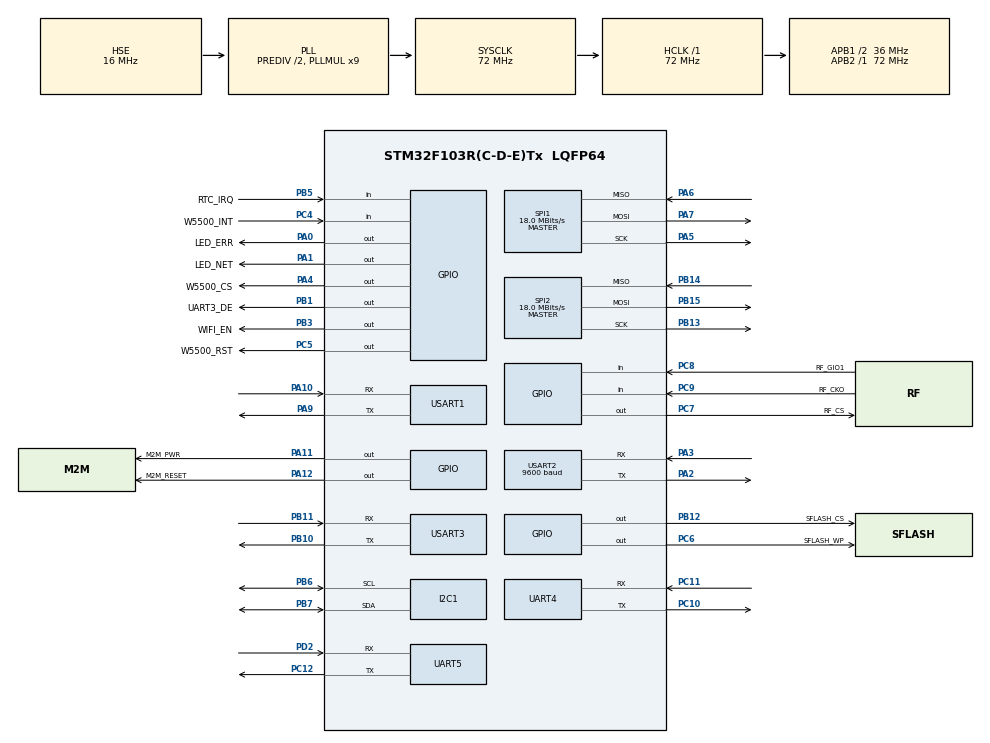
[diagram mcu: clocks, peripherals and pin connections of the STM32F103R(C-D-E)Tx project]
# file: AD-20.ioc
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Dma.Request0=USART1_TX
Dma.Request1=USART3_TX
Dma.Request2=USART2_TX
Dma.Request3=UART4_TX
Dma.UART4_TX.3.Direction=DMA_MEMORY_TO_PERIPH
Dma.UART4_TX.3.Instance=DMA2_Channel5
Dma.UART4_TX.3.MemDataAlignment=DMA_MDATAALIGN_BYTE
Dma.UART4_TX.3.MemInc=DMA_MINC_ENABLE
Dma.UART4_TX.3.Mode=DMA_NORMAL
Dma.UART4_TX.3.PeriphDataAlignment=DMA_PDATAALIGN_BYTE
Dma.UART4_TX.3.PeriphInc=DMA_PINC_DISABLE
Dma.UART4_TX.3.Priority=DMA_PRIORITY_LOW
Dma.USART1_TX.0.Direction=DMA_MEMORY_TO_PERIPH
Dma.USART1_TX.0.Instance=DMA1_Channel4
Dma.USART1_TX.0.MemDataAlignment=DMA_MDATAALIGN_BYTE
Dma.USART1_TX.0.MemInc=DMA_MINC_ENABLE
Dma.USART1_TX.0.Mode=DMA_NORMAL
Dma.USART1_TX.0.PeriphDataAlignment=DMA_PDATAALIGN_BYTE
Dma.USART1_TX.0.PeriphInc=DMA_PINC_DISABLE
Dma.USART1_TX.0.Priority=DMA_PRIORITY_LOW
Dma.USART2_TX.2.Direction=DMA_MEMORY_TO_PERIPH
Dma.USART2_TX.2.Instance=DMA1_Channel7
Dma.USART2_TX.2.MemDataAlignment=DMA_MDATAALIGN_BYTE
Dma.USART2_TX.2.MemInc=DMA_MINC_ENABLE
Dma.USART2_TX.2.Mode=DMA_NORMAL
Dma.USART2_TX.2.PeriphDataAlignment=DMA_PDATAALIGN_BYTE
Dma.USART2_TX.2.PeriphInc=DMA_PINC_DISABLE
Dma.USART2_TX.2.Priority=DMA_PRIORITY_LOW
Dma.USART3_TX.1.Direction=DMA_MEMORY_TO_PERIPH
Dma.USART3_TX.1.Instance=DMA1_Channel2
Dma.USART3_TX.1.MemDataAlignment=DMA_MDATAALIGN_BYTE
Dma.USART3_TX.1.MemInc=DMA_MINC_ENABLE
Dma.USART3_TX.1.Mode=DMA_NORMAL
Dma.USART3_TX.1.PeriphDataAlignment=DMA_PDATAALIGN_BYTE
Dma.USART3_TX.1.PeriphInc=DMA_PINC_DISABLE
Dma.USART3_TX.1.Priority=DMA_PRIORITY_LOW
FREERTOS.Tasks01=defaultTask,0,128,StartDefaultTask,Default,NULL
FREERTOS.configCHECK_FOR_STACK_OVERFLOW=2
FREERTOS.configQUEUE_REGISTRY_SIZE=16
FREERTOS.configTOTAL_HEAP_SIZE=30720
FREERTOS.configUSE_IDLE_HOOK=1
FREERTOS.configUSE_MALLOC_FAILED_HOOK=1
FREERTOS.configUSE_RECURSIVE_MUTEXES=1
FREERTOS.configUSE_TICK_HOOK=1
IWDG.Prescaler=IWDG_PRESCALER_128
Mcu.Family=STM32F1
Mcu.Name=STM32F103R(C-D-E)Tx
Mcu.Package=LQFP64
NVIC.DMA1_Channel2_IRQn=true\:5\:0\:false\:false\:true\:true\:false
NVIC.DMA1_Channel4_IRQn=true\:5\:0\:false\:false\:true\:true\:false
NVIC.DMA1_Channel7_IRQn=true\:5\:0\:false\:false\:true\:true\:false
NVIC.DMA2_Channel4_5_IRQn=true\:5\:0\:false\:false\:true\:true\:false
NVIC.PriorityGroup=NVIC_PRIORITYGROUP_4
NVIC.TIM8_UP_IRQn=true\:0\:0\:false\:false\:true\:false\:false
NVIC.TimeBase=TIM8_UP_IRQn
NVIC.TimeBaseIP=TIM8
NVIC.UART4_IRQn=true\:5\:0\:false\:false\:true\:true\:true
NVIC.UART5_IRQn=true\:5\:0\:false\:false\:true\:true\:true
NVIC.USART1_IRQn=true\:5\:0\:false\:false\:true\:true\:true
NVIC.USART2_IRQn=true\:5\:0\:false\:false\:true\:true\:true
NVIC.USART3_IRQn=true\:5\:0\:false\:false\:true\:true\:true
PA0-WKUP.GPIO_Label=LED_ERR
PA0-WKUP.Signal=GPIO_Output
PA1.GPIO_Label=LED_NET
PA1.Signal=GPIO_Output
PA10.Mode=Asynchronous
PA10.Signal=USART1_RX
PA11.GPIO_Label=M2M_PWR
PA11.GPIO_ModeDefaultOutputPP=GPIO_MODE_OUTPUT_OD
PA11.GPIO_Speed=GPIO_SPEED_FREQ_HIGH
PA11.PinState=GPIO_PIN_SET
PA11.Signal=GPIO_Output
PA12.GPIO_Label=M2M_RESET
PA12.GPIO_ModeDefaultOutputPP=GPIO_MODE_OUTPUT_OD
PA12.GPIO_Speed=GPIO_SPEED_FREQ_HIGH
PA12.PinState=GPIO_PIN_SET
PA12.Signal=GPIO_Output
PA13.Mode=Serial_Wire
PA13.Signal=SYS_JTMS-SWDIO
PA14.Mode=Serial_Wire
PA14.Signal=SYS_JTCK-SWCLK
PA2.Mode=Asynchronous
PA2.Signal=USART2_TX
PA3.Mode=Asynchronous
PA3.Signal=USART2_RX
PA4.GPIO_Label=W5500_CS
PA4.GPIO_Speed=GPIO_SPEED_FREQ_HIGH
PA4.Signal=GPIO_Output
PA5.Mode=Full_Duplex_Master
PA5.Signal=SPI1_SCK
PA6.Mode=Full_Duplex_Master
PA6.Signal=SPI1_MISO
PA7.Mode=Full_Duplex_Master
PA7.Signal=SPI1_MOSI
PA9.Mode=Asynchronous
PA9.Signal=USART1_TX
PB1.GPIO_Label=UART3_DE
PB1.Signal=GPIO_Output
PB10.Mode=Asynchronous
PB10.Signal=USART3_TX
PB11.Mode=Asynchronous
PB11.Signal=USART3_RX
PB12.GPIO_Label=SFLASH_CS
PB12.GPIO_Speed=GPIO_SPEED_FREQ_HIGH
PB12.Signal=GPIO_Output
PB13.Mode=Full_Duplex_Master
PB13.Signal=SPI2_SCK
PB14.Mode=Full_Duplex_Master
PB14.Signal=SPI2_MISO
PB15.Mode=Full_Duplex_Master
PB15.Signal=SPI2_MOSI
PB3.GPIO_Label=WIFI_EN
PB3.GPIO_Speed=GPIO_SPEED_FREQ_HIGH
PB3.Signal=GPIO_Output
PB5.GPIO_Label=RTC_IRQ
PB5.GPIO_PuPd=GPIO_PULLUP
PB5.Signal=GPIO_Input
PB6.Mode=I2C
PB6.Signal=I2C1_SCL
PB7.Mode=I2C
PB7.Signal=I2C1_SDA
PC10.Mode=Asynchronous
PC10.Signal=UART4_TX
PC11.Mode=Asynchronous
PC11.Signal=UART4_RX
PC12.Mode=Asynchronous
PC12.Signal=UART5_TX
PC4.GPIO_Label=W5500_INT
PC4.GPIO_PuPd=GPIO_PULLUP
PC4.Signal=GPIO_Input
PC5.GPIO_Label=W5500_RST
PC5.GPIO_Speed=GPIO_SPEED_FREQ_HIGH
PC5.Signal=GPIO_Output
PC6.GPIO_Label=SFLASH_WP
PC6.Signal=GPIO_Output
PC7.GPIO_Label=RF_CS
PC7.GPIO_Speed=GPIO_SPEED_FREQ_HIGH
PC7.Signal=GPIO_Output
PC8.GPIO_Label=RF_GIO1
PC8.Signal=GPIO_Input
PC9.GPIO_Label=RF_CKO
PC9.Signal=GPIO_Input
PD0-OSC_IN.Mode=HSE-External-Oscillator
PD0-OSC_IN.Signal=RCC_OSC_IN
PD1-OSC_OUT.Mode=HSE-External-Oscillator
PD1-OSC_OUT.Signal=RCC_OSC_OUT
PD2.Mode=Asynchronous
PD2.Signal=UART5_RX
ProjectManager.HeapSize=0x200
ProjectManager.StackSize=0x400
ProjectManager.TargetToolchain=EWARM V7
RCC.AHBFreq_Value=72000000
RCC.APB1CLKDivider=RCC_HCLK_DIV2
RCC.APB1Freq_Value=36000000
RCC.APB1TimFreq_Value=72000000
RCC.APB2Freq_Value=72000000
RCC.APB2TimFreq_Value=72000000
RCC.HCLKFreq_Value=72000000
RCC.HSEDivPLL=RCC_HSE_PREDIV_DIV2
RCC.HSE_VALUE=16000000
RCC.PLLMUL=RCC_PLL_MUL9
RCC.PLLSourceVirtual=RCC_PLLSOURCE_HSE
RCC.SYSCLKFreq_VALUE=72000000
RCC.SYSCLKSource=RCC_SYSCLKSOURCE_PLLCLK
RCC.USBFreq_Value=72000000
SPI1.BaudRatePrescaler=SPI_BAUDRATEPRESCALER_4
SPI1.CalculateBaudRate=18.0 MBits/s
SPI1.Direction=SPI_DIRECTION_2LINES
SPI1.Mode=SPI_MODE_MASTER
SPI1.VirtualType=VM_MASTER
SPI2.BaudRatePrescaler=SPI_BAUDRATEPRESCALER_2
SPI2.CalculateBaudRate=18.0 MBits/s
SPI2.Direction=SPI_DIRECTION_2LINES
SPI2.Mode=SPI_MODE_MASTER
SPI2.VirtualType=VM_MASTER
UART4.VirtualMode=Asynchronous
UART5.VirtualMode=Asynchronous
USART1.VirtualMode=VM_ASYNC
USART2.BaudRate=9600
USART2.VirtualMode=VM_ASYNC
USART3.VirtualMode=VM_ASYNC
VP_CRC_VS_CRC.Mode=CRC_Activate
VP_FREERTOS_VS_ENABLE.Mode=Enabled
VP_IWDG_VS_IWDG.Mode=IWDG_Activate
VP_SYS_VS_tim8.Mode=TIM8
board=custom

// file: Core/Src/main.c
/**
 ******************************************************************************
 * @file           : main.c
 * @brief          : Main program body
 ******************************************************************************
 * This notice applies to any and all portions of this file
 * that are not between comment pairs USER CODE BEGIN and
 * USER CODE END. Other portions of this file, whether
 * inserted by the user or by software development tools
 * are owned by their respective copyright owners.
 *
 * Copyright (c) 2018 STMicroelectronics International N.V.
 * All rights reserved.
 *
 * Redistribution and use in source and binary forms, with or without
 * modification, are permitted, provided that the following conditions are met:
 *
 * 1. Redistribution of source code must retain the above copyright notice,
 *    this list of conditions and the following disclaimer.
 * 2. Redistributions in binary form must reproduce the above copyright notice,
 *    this list of conditions and the following disclaimer in the documentation
 *    and/or other materials provided with the distribution.
 * 3. Neither the name of STMicroelectronics nor the names of other
 *    contributors to this software may be used to endorse or promote products
 *    derived from this software without specific written permission.
 * 4. This software, including modifications and/or derivative works of this
 *    software, must execute solely and exclusively on microcontroller or
 *    microprocessor devices manufactured by or for STMicroelectronics.
 * 5. Redistribution and use of this software other than as permitted under
 *    this license is void and will automatically terminate your rights under
 *    this license.
 *
 * THIS SOFTWARE IS PROVIDED BY STMICROELECTRONICS AND CONTRIBUTORS "AS IS"
 * AND ANY EXPRESS, IMPLIED OR STATUTORY WARRANTIES, INCLUDING, BUT NOT
 * LIMITED TO, THE IMPLIED WARRANTIES OF MERCHANTABILITY, FITNESS FOR A
 * PARTICULAR PURPOSE AND NON-INFRINGEMENT OF THIRD PARTY INTELLECTUAL PROPERTY
 * RIGHTS ARE DISCLAIMED TO THE FULLEST EXTENT PERMITTED BY LAW. IN NO EVENT
 * SHALL STMICROELECTRONICS OR CONTRIBUTORS BE LIABLE FOR ANY DIRECT, INDIRECT,
 * INCIDENTAL, SPECIAL, EXEMPLARY, OR CONSEQUENTIAL DAMAGES (INCLUDING, BUT NOT
 * LIMITED TO, PROCUREMENT OF SUBSTITUTE GOODS OR SERVICES; LOSS OF USE, DATA,
 * OR PROFITS; OR BUSINESS INTERRUPTION) HOWEVER CAUSED AND ON ANY THEORY OF
 * LIABILITY, WHETHER IN CONTRACT, STRICT LIABILITY, OR TORT (INCLUDING
 * NEGLIGENCE OR OTHERWISE) ARISING IN ANY WAY OUT OF THE USE OF THIS SOFTWARE,
 * EVEN IF ADVISED OF THE POSSIBILITY OF SUCH DAMAGE.
 *
 ******************************************************************************
 */
#include "main.h"
#include "stm32f1xx_hal.h"
#include "cmsis_os.h"

/* USER CODE BEGIN Includes */
#include "user_comm.h"
/* USER CODE END Includes */

CRC_HandleTypeDef hcrc;

I2C_HandleTypeDef hi2c1;

IWDG_HandleTypeDef hiwdg;

SPI_HandleTypeDef hspi1;
SPI_HandleTypeDef hspi2;

UART_HandleTypeDef huart4;
UART_HandleTypeDef huart5;
UART_HandleTypeDef huart1;
UART_HandleTypeDef huart2;
UART_HandleTypeDef huart3;
DMA_HandleTypeDef hdma_uart4_tx;
DMA_HandleTypeDef hdma_usart1_tx;
DMA_HandleTypeDef hdma_usart2_tx;
DMA_HandleTypeDef hdma_usart3_tx;
TIM_HandleTypeDef htim3;
osThreadId defaultTaskHandle;

/* USER CODE BEGIN PV */
/* Private variables ---------------------------------------------------------*/

/* USER CODE END PV */

void SystemClock_Config(void);
static void MX_GPIO_Init(void);
static void MX_DMA_Init(void);
static void MX_USART2_UART_Init(void);
static void MX_SPI1_Init(void);
static void MX_USART3_UART_Init(void);
static void MX_SPI2_Init(void);
static void MX_USART1_UART_Init(void);
static void MX_UART5_Init(void);
static void MX_I2C1_Init(void);
static void MX_UART4_Init(void);
static void MX_IWDG_Init(void);
static void MX_CRC_Init(void);
static void MX_TIM3_Init(void);

void StartDefaultTask(void const *argument);

/* USER CODE BEGIN PFP */
/* Private function prototypes -----------------------------------------------*/

/* USER CODE END PFP */

int main(void) {
	/* USER CODE BEGIN 1 */
    //transLabelId(1234567);
	/* USER CODE END 1 */

	/* MCU Configuration----------------------------------------------------------*/

	/* Reset of all peripherals, Initializes the Flash interface and the Systick. */
	HAL_Init();

	/* Configure the system clock */
	SystemClock_Config();

	/* Initialize all configured peripherals */
	MX_GPIO_Init();

	MX_DMA_Init();
	MX_USART2_UART_Init();
	MX_SPI1_Init();
	MX_USART3_UART_Init();
	MX_SPI2_Init();
	MX_USART1_UART_Init();
	MX_UART5_Init();
	MX_I2C1_Init();
	MX_UART4_Init();
	MX_IWDG_Init();
	//MX_TIM3_Init();

	//MX_CRC_Init();

	/* Create the thread(s) */
	/* definition and creation of defaultTask */
	osThreadDef(defaultTask, StartDefaultTask, osPriorityNormal, 0, 128)
	;
	defaultTaskHandle = osThreadCreate(osThread(defaultTask), NULL);

	/* Start scheduler */
	osKernelStart();

	/* We should never get here as control is now taken by the scheduler */

	/* Infinite loop */
	while (1) {

	}

}

void SystemClock_Config(void) {

	RCC_OscInitTypeDef RCC_OscInitStruct;
	RCC_ClkInitTypeDef RCC_ClkInitStruct;

	/**Initializes the CPU, AHB and APB busses clocks
	 */
	RCC_OscInitStruct.OscillatorType = RCC_OSCILLATORTYPE_LSI | RCC_OSCILLATORTYPE_HSE;
	RCC_OscInitStruct.HSEState = RCC_HSE_ON;
	RCC_OscInitStruct.HSEPredivValue = RCC_HSE_PREDIV_DIV2;
	RCC_OscInitStruct.HSIState = RCC_HSI_ON;
	RCC_OscInitStruct.LSIState = RCC_LSI_ON;
	RCC_OscInitStruct.PLL.PLLState = RCC_PLL_ON;
	RCC_OscInitStruct.PLL.PLLSource = RCC_PLLSOURCE_HSE;
	RCC_OscInitStruct.PLL.PLLMUL = RCC_PLL_MUL9;
	if (HAL_RCC_OscConfig(&RCC_OscInitStruct) != HAL_OK) {
		_Error_Handler(__FILE__, __LINE__);
	}

	/**Initializes the CPU, AHB and APB busses clocks
	 */
	RCC_ClkInitStruct.ClockType = RCC_CLOCKTYPE_HCLK | RCC_CLOCKTYPE_SYSCLK | RCC_CLOCKTYPE_PCLK1 | RCC_CLOCKTYPE_PCLK2;
	RCC_ClkInitStruct.SYSCLKSource = RCC_SYSCLKSOURCE_PLLCLK;
	RCC_ClkInitStruct.AHBCLKDivider = RCC_SYSCLK_DIV1;
	RCC_ClkInitStruct.APB1CLKDivider = RCC_HCLK_DIV2;
	RCC_ClkInitStruct.APB2CLKDivider = RCC_HCLK_DIV1;

	if (HAL_RCC_ClockConfig(&RCC_ClkInitStruct, FLASH_LATENCY_2) != HAL_OK) {
		_Error_Handler(__FILE__, __LINE__);
	}

	/**Configure the Systick interrupt time
	 */
	HAL_SYSTICK_Config(HAL_RCC_GetHCLKFreq() / 1000);

	/**Configure the Systick
	 */
	HAL_SYSTICK_CLKSourceConfig(SYSTICK_CLKSOURCE_HCLK);

	/* SysTick_IRQn interrupt configuration */
	HAL_NVIC_SetPriority(SysTick_IRQn, 15, 0);
}

/* CRC init function */
static void MX_CRC_Init(void) {

	hcrc.Instance = CRC;
	if (HAL_CRC_Init(&hcrc) != HAL_OK) {
		_Error_Handler(__FILE__, __LINE__);
	}

}

/* I2C1 init function */
static void MX_I2C1_Init(void) {

	hi2c1.Instance = I2C1;
	hi2c1.Init.ClockSpeed = 100000;
	hi2c1.Init.DutyCycle = I2C_DUTYCYCLE_2;
	hi2c1.Init.OwnAddress1 = 0;
	hi2c1.Init.AddressingMode = I2C_ADDRESSINGMODE_7BIT;
	hi2c1.Init.DualAddressMode = I2C_DUALADDRESS_DISABLE;
	hi2c1.Init.OwnAddress2 = 0;
	hi2c1.Init.GeneralCallMode = I2C_GENERALCALL_DISABLE;
	hi2c1.Init.NoStretchMode = I2C_NOSTRETCH_DISABLE;
	if (HAL_I2C_Init(&hi2c1) != HAL_OK) {
		_Error_Handler(__FILE__, __LINE__);
	}

}

#if 0
/* TIM3 init function */
static void MX_TIM3_Init(void)
{

  TIM_MasterConfigTypeDef sMasterConfig;
  TIM_OC_InitTypeDef sConfigOC;

  htim3.Instance = TIM3;
  htim3.Init.Prescaler = 0;
  htim3.Init.CounterMode = TIM_COUNTERMODE_UP;
  htim3.Init.Period = 0;
  htim3.Init.ClockDivision = TIM_CLOCKDIVISION_DIV1;
  htim3.Init.AutoReloadPreload = TIM_AUTORELOAD_PRELOAD_DISABLE;
  if (HAL_TIM_OC_Init(&htim3) != HAL_OK)
  {
    _Error_Handler(__FILE__, __LINE__);
  }

  sMasterConfig.MasterOutputTrigger = TIM_TRGO_RESET;
  sMasterConfig.MasterSlaveMode = TIM_MASTERSLAVEMODE_DISABLE;
  if (HAL_TIMEx_MasterConfigSynchronization(&htim3, &sMasterConfig) != HAL_OK)
  {
    _Error_Handler(__FILE__, __LINE__);
  }

  sConfigOC.OCMode = TIM_OCMODE_TIMING;
  sConfigOC.Pulse = 0;
  sConfigOC.OCPolarity = TIM_OCPOLARITY_HIGH;
  sConfigOC.OCFastMode = TIM_OCFAST_DISABLE;
  if (HAL_TIM_OC_ConfigChannel(&htim3, &sConfigOC, TIM_CHANNEL_3) != HAL_OK)
  {
    _Error_Handler(__FILE__, __LINE__);
  }

  HAL_TIM_MspPostInit(&htim3);

}
#endif

/* IWDG init function */
static void MX_IWDG_Init(void) {

	hiwdg.Instance = IWDG;
	hiwdg.Init.Prescaler = IWDG_PRESCALER_128;
	hiwdg.Init.Reload = 4095;
	if (HAL_IWDG_Init(&hiwdg) != HAL_OK) {
		_Error_Handler(__FILE__, __LINE__);
	}

}

/* SPI1 init function */
static void MX_SPI1_Init(void) {

	/* SPI1 parameter configuration*/
	hspi1.Instance = SPI1;
	hspi1.Init.Mode = SPI_MODE_MASTER;
	hspi1.Init.Direction = SPI_DIRECTION_2LINES;
	hspi1.Init.DataSize = SPI_DATASIZE_8BIT;
	hspi1.Init.CLKPolarity = SPI_POLARITY_LOW;
	hspi1.Init.CLKPhase = SPI_PHASE_1EDGE;
	hspi1.Init.NSS = SPI_NSS_SOFT;
	hspi1.Init.BaudRatePrescaler = SPI_BAUDRATEPRESCALER_4;
	hspi1.Init.FirstBit = SPI_FIRSTBIT_MSB;
	hspi1.Init.TIMode = SPI_TIMODE_DISABLE;
	hspi1.Init.CRCCalculation = SPI_CRCCALCULATION_DISABLE;
	hspi1.Init.CRCPolynomial = 10;
	if (HAL_SPI_Init(&hspi1) != HAL_OK) {
		_Error_Handler(__FILE__, __LINE__);
	}

}

/* SPI2 init function */
static void MX_SPI2_Init(void) {

	/* SPI2 parameter configuration*/
	hspi2.Instance = SPI2;
	hspi2.Init.Mode = SPI_MODE_MASTER;
	hspi2.Init.Direction = SPI_DIRECTION_2LINES;
	hspi2.Init.DataSize = SPI_DATASIZE_8BIT;
	hspi2.Init.CLKPolarity = SPI_POLARITY_LOW;
	hspi2.Init.CLKPhase = SPI_PHASE_1EDGE;
	hspi2.Init.NSS = SPI_NSS_SOFT;
	hspi2.Init.BaudRatePrescaler = SPI_BAUDRATEPRESCALER_2;
	hspi2.Init.FirstBit = SPI_FIRSTBIT_MSB;
	hspi2.Init.TIMode = SPI_TIMODE_DISABLE;
	hspi2.Init.CRCCalculation = SPI_CRCCALCULATION_DISABLE;
	hspi2.Init.CRCPolynomial = 10;
	if (HAL_SPI_Init(&hspi2) != HAL_OK) {
		_Error_Handler(__FILE__, __LINE__);
	}

}

/* UART4 init function */
static void MX_UART4_Init(void) {

	huart4.Instance = UART4;
	huart4.Init.BaudRate = 115200;
	huart4.Init.WordLength = UART_WORDLENGTH_8B;
	huart4.Init.StopBits = UART_STOPBITS_1;
	huart4.Init.Parity = UART_PARITY_NONE;
	huart4.Init.Mode = UART_MODE_TX_RX;
	huart4.Init.HwFlowCtl = UART_HWCONTROL_NONE;
	huart4.Init.OverSampling = UART_OVERSAMPLING_16;
	if (HAL_UART_Init(&huart4) != HAL_OK) {
		_Error_Handler(__FILE__, __LINE__);
	}

}

/* UART5 init function */
static void MX_UART5_Init(void) {

	huart5.Instance = UART5;
	huart5.Init.BaudRate = 115200;
	huart5.Init.WordLength = UART_WORDLENGTH_8B;
	huart5.Init.StopBits = UART_STOPBITS_1;
	huart5.Init.Parity = UART_PARITY_NONE;
	huart5.Init.Mode = UART_MODE_TX_RX;
	huart5.Init.HwFlowCtl = UART_HWCONTROL_NONE;
	huart5.Init.OverSampling = UART_OVERSAMPLING_16;
	if (HAL_UART_Init(&huart5) != HAL_OK) {
		_Error_Handler(__FILE__, __LINE__);
	}

}

/* USART1 init function */
static void MX_USART1_UART_Init(void) {

	huart1.Instance = USART1;
	huart1.Init.BaudRate = 115200;
	huart1.Init.WordLength = UART_WORDLENGTH_8B;
	huart1.Init.StopBits = UART_STOPBITS_1;
	huart1.Init.Parity = UART_PARITY_NONE;
	huart1.Init.Mode = UART_MODE_TX_RX;
	huart1.Init.HwFlowCtl = UART_HWCONTROL_NONE;
	huart1.Init.OverSampling = UART_OVERSAMPLING_16;
	if (HAL_UART_Init(&huart1) != HAL_OK) {
		_Error_Handler(__FILE__, __LINE__);
	}

}

/* USART2 init function */
static void MX_USART2_UART_Init(void) {

	huart2.Instance = USART2;
	huart2.Init.BaudRate = 9600;
	huart2.Init.WordLength = UART_WORDLENGTH_8B;
	huart2.Init.StopBits = UART_STOPBITS_1;
	huart2.Init.Parity = UART_PARITY_NONE;
	huart2.Init.Mode = UART_MODE_TX_RX;
	huart2.Init.HwFlowCtl = UART_HWCONTROL_NONE;
	huart2.Init.OverSampling = UART_OVERSAMPLING_16;
	if (HAL_UART_Init(&huart2) != HAL_OK) {
		_Error_Handler(__FILE__, __LINE__);
	}

}

/* USART3 init function */
static void MX_USART3_UART_Init(void) {

	huart3.Instance = USART3;
	huart3.Init.BaudRate = 115200;
	huart3.Init.WordLength = UART_WORDLENGTH_8B;
	huart3.Init.StopBits = UART_STOPBITS_1;
	huart3.Init.Parity = UART_PARITY_NONE;
	huart3.Init.Mode = UART_MODE_TX_RX;
	huart3.Init.HwFlowCtl = UART_HWCONTROL_NONE;
	huart3.Init.OverSampling = UART_OVERSAMPLING_16;
	if (HAL_UART_Init(&huart3) != HAL_OK) {
		_Error_Handler(__FILE__, __LINE__);
	}

}

static void MX_DMA_Init(void) {
	/* DMA controller clock enable */
	__HAL_RCC_DMA1_CLK_ENABLE();
	__HAL_RCC_DMA2_CLK_ENABLE();

	/* DMA interrupt init */
	/* DMA1_Channel2_IRQn interrupt configuration */
	HAL_NVIC_SetPriority(DMA1_Channel2_IRQn, 5, 0);
	HAL_NVIC_EnableIRQ(DMA1_Channel2_IRQn);
	/* DMA1_Channel4_IRQn interrupt configuration */
	HAL_NVIC_SetPriority(DMA1_Channel4_IRQn, 5, 0);
	HAL_NVIC_EnableIRQ(DMA1_Channel4_IRQn);
	/* DMA1_Channel7_IRQn interrupt configuration */
	HAL_NVIC_SetPriority(DMA1_Channel7_IRQn, 5, 0);
	HAL_NVIC_EnableIRQ(DMA1_Channel7_IRQn);
	/* DMA2_Channel4_5_IRQn interrupt configuration */
	HAL_NVIC_SetPriority(DMA2_Channel4_5_IRQn, 5, 0);
	HAL_NVIC_EnableIRQ(DMA2_Channel4_5_IRQn);

}

/** Configure pins as
 * Analog
 * Input
 * Output
 * EVENT_OUT
 * EXTI
 */
static void MX_GPIO_Init(void) {

	GPIO_InitTypeDef GPIO_InitStruct;

	/* GPIO Ports Clock Enable */
	__HAL_RCC_GPIOD_CLK_ENABLE();
	__HAL_RCC_GPIOA_CLK_ENABLE();
	__HAL_RCC_GPIOC_CLK_ENABLE();
	__HAL_RCC_GPIOB_CLK_ENABLE();

	/*Configure GPIO pin Output Level */
	//HAL_GPIO_WritePin(GPIOA, LED_ERR_Pin|LED_NET_Pin|W5500_CS_Pin, GPIO_PIN_RESET);
	/*Configure GPIO pin Output Level */
	//HAL_GPIO_WritePin(GPIOC, W5500_RST_Pin|SFLASH_WP_Pin|RF_CS_Pin, GPIO_PIN_RESET);
	/*Configure GPIO pin Output Level */
	//HAL_GPIO_WritePin(GPIOB, UART3_DE_Pin|SFLASH_CS_Pin|WIFI_EN_Pin, GPIO_PIN_RESET);
	HAL_GPIO_WritePin(GPIOB, UART3_DE_Pin | SFLASH_CS_Pin, GPIO_PIN_RESET);

	/*Configure GPIO pin Output Level */
	//HAL_GPIO_WritePin(GPIOA, M2M_PWR_Pin|M2M_RESET_Pin, GPIO_PIN_SET);
	// 4G模块的KEY先拉低
	HAL_GPIO_WritePin(GPIOA, M4G_PWRKEY_Pin, GPIO_PIN_RESET);

	// 4G模块的电源先拉低
	HAL_GPIO_WritePin(GPIOB, M4G_EN_Pin, GPIO_PIN_RESET);

	/*Configure GPIO pins : LED_ERR_Pin LED_NET_Pin */
	GPIO_InitStruct.Pin = LED_ERR_Pin | LED_NET_Pin;
	GPIO_InitStruct.Mode = GPIO_MODE_OUTPUT_PP;
	GPIO_InitStruct.Pull = GPIO_NOPULL;
	GPIO_InitStruct.Speed = GPIO_SPEED_FREQ_LOW;
	HAL_GPIO_Init(GPIOA, &GPIO_InitStruct);

	/*Configure GPIO pin : W5500_CS_Pin */
	GPIO_InitStruct.Pin = W5500_CS_Pin;
	GPIO_InitStruct.Mode = GPIO_MODE_OUTPUT_PP;
	GPIO_InitStruct.Pull = GPIO_NOPULL;
	GPIO_InitStruct.Speed = GPIO_SPEED_FREQ_HIGH;
	HAL_GPIO_Init(W5500_CS_GPIO_Port, &GPIO_InitStruct);

	/*Configure GPIO pin : W5500_INT_Pin */
	GPIO_InitStruct.Pin = W5500_INT_Pin;
	GPIO_InitStruct.Mode = GPIO_MODE_INPUT;
	GPIO_InitStruct.Pull = GPIO_PULLUP;
	HAL_GPIO_Init(W5500_INT_GPIO_Port, &GPIO_InitStruct);

	/*Configure GPIO pins : W5500_RST_Pin RF_CS_Pin */
	GPIO_InitStruct.Pin = W5500_RST_Pin | RF_CS_Pin;
	GPIO_InitStruct.Mode = GPIO_MODE_OUTPUT_PP;
	GPIO_InitStruct.Pull = GPIO_NOPULL;
	GPIO_InitStruct.Speed = GPIO_SPEED_FREQ_HIGH;
	HAL_GPIO_Init(GPIOC, &GPIO_InitStruct);

	/*Configure GPIO pin : UART3_DE_Pin */
	GPIO_InitStruct.Pin = UART3_DE_Pin;
	GPIO_InitStruct.Mode = GPIO_MODE_OUTPUT_PP;
	GPIO_InitStruct.Pull = GPIO_NOPULL;
	GPIO_InitStruct.Speed = GPIO_SPEED_FREQ_LOW;
	HAL_GPIO_Init(UART3_DE_GPIO_Port, &GPIO_InitStruct);

	/*Configure GPIO pins : SFLASH_CS_Pin WIFI_EN_Pin */
	GPIO_InitStruct.Pin = SFLASH_CS_Pin;
	//GPIO_InitStruct.Pin = SFLASH_CS_Pin|WIFI_EN_Pin;
	GPIO_InitStruct.Mode = GPIO_MODE_OUTPUT_PP;
	GPIO_InitStruct.Pull = GPIO_NOPULL;
	GPIO_InitStruct.Speed = GPIO_SPEED_FREQ_HIGH;
	HAL_GPIO_Init(GPIOB, &GPIO_InitStruct);

	/*Configure GPIO pin : SFLASH_WP_Pin */
	GPIO_InitStruct.Pin = SFLASH_WP_Pin;
	GPIO_InitStruct.Mode = GPIO_MODE_OUTPUT_PP;
	GPIO_InitStruct.Pull = GPIO_NOPULL;
	GPIO_InitStruct.Speed = GPIO_SPEED_FREQ_LOW;
	HAL_GPIO_Init(SFLASH_WP_GPIO_Port, &GPIO_InitStruct);

#if 0
  /*Configure GPIO pins : RF_GIO1_Pin RF_CKO_Pin */
  GPIO_InitStruct.Pin = RF_GIO1_Pin|RF_CKO_Pin;
  GPIO_InitStruct.Mode = GPIO_MODE_INPUT;
  GPIO_InitStruct.Pull = GPIO_NOPULL;
  HAL_GPIO_Init(GPIOC, &GPIO_InitStruct);

  /*Configure GPIO pins : M2M_PWR_Pin M2M_RESET_Pin */
  GPIO_InitStruct.Pin = M2M_PWR_Pin|M2M_RESET_Pin;
  GPIO_InitStruct.Mode = GPIO_MODE_OUTPUT_OD;
  GPIO_InitStruct.Pull = GPIO_NOPULL;
  GPIO_InitStruct.Speed = GPIO_SPEED_FREQ_HIGH;
  HAL_GPIO_Init(GPIOA, &GPIO_InitStruct);

  /*Configure GPIO pin : RTC_IRQ_Pin */
  GPIO_InitStruct.Pin = RTC_IRQ_Pin;
  GPIO_InitStruct.Mode = GPIO_MODE_INPUT;
  GPIO_InitStruct.Pull = GPIO_PULLUP;
  HAL_GPIO_Init(RTC_IRQ_GPIO_Port, &GPIO_InitStruct);
#endif

	// 4G模块的EN脚初始化
	GPIO_InitStruct.Pin = M4G_PWRKEY_Pin;
	GPIO_InitStruct.Mode = GPIO_MODE_OUTPUT_PP;
	GPIO_InitStruct.Pull = GPIO_NOPULL;
	GPIO_InitStruct.Speed = GPIO_SPEED_FREQ_LOW;
	HAL_GPIO_Init(GPIOC, &GPIO_InitStruct);

	GPIO_InitStruct.Pin = M4G_EN_Pin;
	GPIO_InitStruct.Mode = GPIO_MODE_OUTPUT_PP;
	GPIO_InitStruct.Pull = GPIO_NOPULL;
	GPIO_InitStruct.Speed = GPIO_SPEED_FREQ_LOW;
	HAL_GPIO_Init(GPIOB, &GPIO_InitStruct);

	// 蜂鸣器引脚
	GPIO_InitStruct.Pin = BEEP_EN_Pin;
	GPIO_InitStruct.Mode = GPIO_MODE_OUTPUT_PP;
	GPIO_InitStruct.Pull = GPIO_NOPULL;
	GPIO_InitStruct.Speed = GPIO_SPEED_FREQ_LOW;
	HAL_GPIO_Init(GPIOC, &GPIO_InitStruct);

	GPIO_InitStruct.Pin = LED_Pin;
	GPIO_InitStruct.Mode = GPIO_MODE_OUTPUT_PP;
	GPIO_InitStruct.Pull = GPIO_NOPULL;
	GPIO_InitStruct.Speed = GPIO_SPEED_FREQ_LOW;
	HAL_GPIO_Init(GPIOA, &GPIO_InitStruct);

}

void StartDefaultTask(void const *argument) {
	uint16_t i = 0;
	/* USER CODE BEGIN 5 */
	TWDT_DEF(startTask, 30000);
	TWDT_ADD(startTask);
	TWDT_CLEAR(startTask);
#if UART1_RECEVIE_BUFFER_SIZE > 0
	UART_PortConfig(1, &huart1, UART1_RECEVIE_BUFFER_SIZE);
#endif
#if UART2_RECEVIE_BUFFER_SIZE > 0
	UART_PortConfig(2, &huart2, UART2_RECEVIE_BUFFER_SIZE);
#endif
#if UART3_RECEVIE_BUFFER_SIZE > 0
	UART_PortConfig(3, &huart3, UART3_RECEVIE_BUFFER_SIZE);
#endif
#if UART4_RECEVIE_BUFFER_SIZE > 0
	UART_PortConfig(4, &huart4, UART4_RECEVIE_BUFFER_SIZE);
#endif
#if UART5_RECEVIE_BUFFER_SIZE > 0
	UART_PortConfig(5, &huart5, UART5_RECEVIE_BUFFER_SIZE);
#endif

	/*初始化核心驱动*/
	CMD_Init();
	System_Init();
	SFlash_Init(&hspi2);

	HAL_GPIO_WritePin(GPIOC, BEEP_EN_Pin, GPIO_PIN_SET);
	osDelay(200);
	HAL_GPIO_WritePin(GPIOC, BEEP_EN_Pin, GPIO_PIN_RESET);
	osDelay(200);
	HAL_GPIO_WritePin(GPIOC, BEEP_EN_Pin, GPIO_PIN_SET);
	osDelay(200);
	HAL_GPIO_WritePin(GPIOC, BEEP_EN_Pin, GPIO_PIN_RESET);
	osDelay(200);
	HAL_GPIO_WritePin(GPIOC, BEEP_EN_Pin, GPIO_PIN_SET);
	osDelay(200);
	HAL_GPIO_WritePin(GPIOC, BEEP_EN_Pin, GPIO_PIN_RESET);

	// 外接时钟初始化
	//ExternRTC_Init(&hi2c1);
	//DBG_LOG("SPI flash erase chip begin.");
	SFlash_EraseChip();
	//DBG_LOG("SPI flash erase chip OK.");

	/*初始化系统功能*/
	WorkParam_Init();
	StartLog_Recoder();
	//HTTP_Init();
	//DFU_Init();
	DataSave_Init();

	// 初始化服务
	// TCP_Conn_Init();
	// ProtocolInit();

	M4G_Init();
	/*初始化外设驱动*/
	//WIFI_Init();
	//GPRS_Init();

   	w5500_Init(&hspi1);
  	// MQTT初始化
	MQTT_Conn_Init();
#if 0
    DBG_LOG("Wait for MQTT connect...");

    while(!MQTT_IsConnected()){
        CMD_UART_Read_Poll();
        UART_Refresh_Poll();
        TWDT_CLEAR(startTask);
    }

#endif
    //UART_PortConfig(3, &huart3, UART3_RECEVIE_BUFFER_SIZE);

    /*初始化业务逻辑*/
	Process_Init();

	// 蓝牙模块任务
	bt_Init();

	// Control_Init();
	DBG_LOG("System Start!");
	/* Infinite loop */
	for (;;) {
		osDelay(2);
		CMD_UART_Read_Poll();
		UART_Refresh_Poll();
		LED_FlashPoll();
		//BT_Intercept_Proc();
		//DFU_Poll();
		//Control_Polling();
		TWDT_CLEAR(startTask);
	}
	/* USER CODE END 5 */
}

void HAL_TIM_PeriodElapsedCallback(TIM_HandleTypeDef *htim) {
	if (htim->Instance == TIM8) {
		HAL_IncTick();
	}
}

void _Error_Handler(char *file, int line) {
	while (1) {
	}
}

/************************ (C) COPYRIGHT STMicroelectronics *****END OF FILE****/

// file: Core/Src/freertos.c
/* USER CODE BEGIN Header */
/**
  ******************************************************************************
  * File Name          : freertos.c
  * Description        : Code for freertos applications
  ******************************************************************************
  * This notice applies to any and all portions of this file
  * that are not between comment pairs USER CODE BEGIN and
  * USER CODE END. Other portions of this file, whether
  * inserted by the user or by software development tools
  * are owned by their respective copyright owners.
  *
  * Copyright (c) 2018 STMicroelectronics International N.V.
  * All rights reserved.
  *
  * Redistribution and use in source and binary forms, with or without
  * modification, are permitted, provided that the following conditions are met:
  *
  * 1. Redistribution of source code must retain the above copyright notice,
  *    this list of conditions and the following disclaimer.
  * 2. Redistributions in binary form must reproduce the above copyright notice,
  *    this list of conditions and the following disclaimer in the documentation
  *    and/or other materials provided with the distribution.
  * 3. Neither the name of STMicroelectronics nor the names of other
  *    contributors to this software may be used to endorse or promote products
  *    derived from this software without specific written permission.
  * 4. This software, including modifications and/or derivative works of this
  *    software, must execute solely and exclusively on microcontroller or
  *    microprocessor devices manufactured by or for STMicroelectronics.
  * 5. Redistribution and use of this software other than as permitted under
  *    this license is void and will automatically terminate your rights under
  *    this license.
  *
  * THIS SOFTWARE IS PROVIDED BY STMICROELECTRONICS AND CONTRIBUTORS "AS IS"
  * AND ANY EXPRESS, IMPLIED OR STATUTORY WARRANTIES, INCLUDING, BUT NOT
  * LIMITED TO, THE IMPLIED WARRANTIES OF MERCHANTABILITY, FITNESS FOR A
  * PARTICULAR PURPOSE AND NON-INFRINGEMENT OF THIRD PARTY INTELLECTUAL PROPERTY
  * RIGHTS ARE DISCLAIMED TO THE FULLEST EXTENT PERMITTED BY LAW. IN NO EVENT
  * SHALL STMICROELECTRONICS OR CONTRIBUTORS BE LIABLE FOR ANY DIRECT, INDIRECT,
  * INCIDENTAL, SPECIAL, EXEMPLARY, OR CONSEQUENTIAL DAMAGES (INCLUDING, BUT NOT
  * LIMITED TO, PROCUREMENT OF SUBSTITUTE GOODS OR SERVICES; LOSS OF USE, DATA,
  * OR PROFITS; OR BUSINESS INTERRUPTION) HOWEVER CAUSED AND ON ANY THEORY OF
  * LIABILITY, WHETHER IN CONTRACT, STRICT LIABILITY, OR TORT (INCLUDING
  * NEGLIGENCE OR OTHERWISE) ARISING IN ANY WAY OUT OF THE USE OF THIS SOFTWARE,
  * EVEN IF ADVISED OF THE POSSIBILITY OF SUCH DAMAGE.
  *
  ******************************************************************************
  */
/* USER CODE END Header */

#include "FreeRTOS.h"
#include "task.h"
#include "main.h"

/* USER CODE BEGIN Includes */
#include "user_comm.h"

/* USER CODE END Includes */

/* USER CODE BEGIN Variables */
extern IWDG_HandleTypeDef hiwdg;

/* USER CODE END Variables */

/* Hook prototypes */
void vApplicationIdleHook(void);
void vApplicationTickHook(void);
void vApplicationStackOverflowHook(xTaskHandle xTask, signed char *pcTaskName);
void vApplicationMallocFailedHook(void);

/* USER CODE BEGIN 2 */
void vApplicationIdleHook(void) {
    /* vApplicationIdleHook() will only be called if configUSE_IDLE_HOOK is set
    to 1 in FreeRTOSConfig.h. It will be called on each iteration of the idle
    task. It is essential that code added to this hook function never attempts
    to block in any way (for example, call xQueueReceive() with a block time
    specified, or call vTaskDelay()). If the application makes use of the
    vTaskDelete() API function (as this demo application does) then it is also
    important that vApplicationIdleHook() is permitted to return to its calling
    function, because it is the responsibility of the idle task to clean up
    memory allocated by the kernel to any task that has since been deleted. */
    char *name = NULL;
    name = TaskWDG_IsUpper();
    if (name == NULL) {
        HAL_IWDG_Refresh(&hiwdg);
    } else {
        THROW(name);
        THROW(" task watchdog overflow, system will reset.\r\n");
        HAL_Delay(1000);
    }
}
/* USER CODE END 2 */

/* USER CODE BEGIN 3 */
void vApplicationTickHook(void) {
    /* This function will be called by each tick interrupt if
    configUSE_TICK_HOOK is set to 1 in FreeRTOSConfig.h. User code can be
    added here, but the tick hook is called from an interrupt context, so
    code must not attempt to block, and only the interrupt safe FreeRTOS API
    functions can be used (those that end in FromISR()). */
    char *name = NULL;
    static BOOL save = FALSE;
    name = TaskWDG_Tick();
    if (name != NULL) {
        if (save == FALSE) {
            TaskFault_Save(RTC_ReadTick(), name);
            save = TRUE;
        }
        THROW(name);
        THROW(" task watchdog overflow, system will reset.\r\n");
    }
}
/* USER CODE END 3 */

/* USER CODE BEGIN 4 */
__weak void vApplicationStackOverflowHook(xTaskHandle xTask, signed char *pcTaskName) {
    /* Run time stack overflow checking is performed if
    configCHECK_FOR_STACK_OVERFLOW is defined to 1 or 2. This hook function is
    called if a stack overflow is detected. */
    THROW((char*)pcTaskName);
    THROW(" Task Overflow.!!\r\n");
    HAL_Delay(1000);
}
/* USER CODE END 4 */

/* USER CODE BEGIN 5 */
void vApplicationMallocFailedHook(void) {
    /* vApplicationMallocFailedHook() will only be called if
    configUSE_MALLOC_FAILED_HOOK is set to 1 in FreeRTOSConfig.h. It is a hook
    function that will get called if a call to pvPortMalloc() fails.
    pvPortMalloc() is called internally by the kernel whenever a task, queue,
    timer or semaphore is created. It is also called by various parts of the
    demo application. If heap_1.c or heap_2.c are used, then the size of the
    heap available to pvPortMalloc() is defined by configTOTAL_HEAP_SIZE in
    FreeRTOSConfig.h, and the xPortGetFreeHeapSize() API function can be used
    to query the size of free heap space that remains (although it does not
    provide information on how the remaining heap might be fragmented). */
    static uint16_t failindex = 0;
    failindex++;
    while (failindex > 10) {
        THROW("Memory malloc failed!!\r\n");
        HAL_Delay(1000);
    }
}
/* USER CODE END 5 */

/************************ (C) COPYRIGHT STMicroelectronics *****END OF FILE****/
